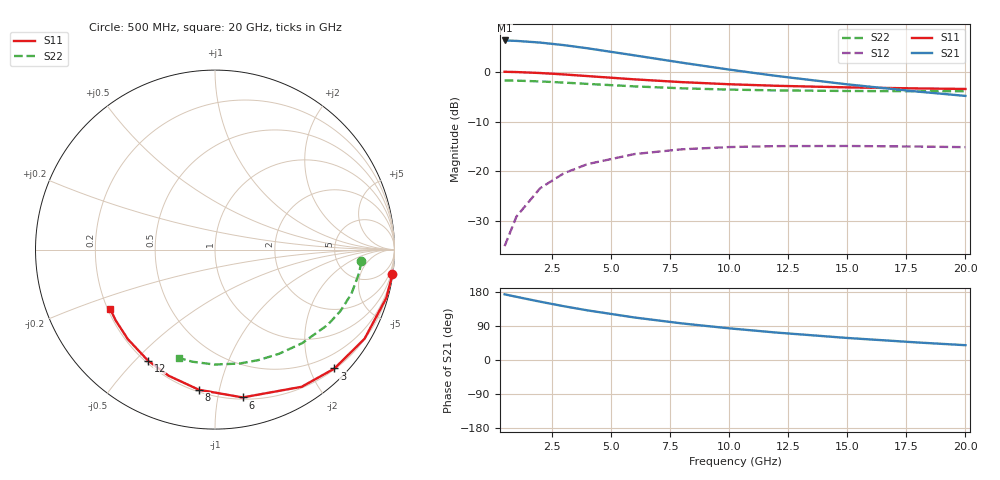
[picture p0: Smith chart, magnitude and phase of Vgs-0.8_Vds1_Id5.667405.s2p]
# Hz S RI R 50
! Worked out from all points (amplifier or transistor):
!   12 points, 500 MHz to 20 GHz, reference 50 ohm
!   highest |S21| = 6.3 dB at 500 MHz (marker M1)
!   |S21| within 3 dB of that: start of sweep to 6.01 GHz
!   unconditionally stable (mu >= 1): 13.79 GHz to end of sweep
!   at 2 GHz: K = 0.13, MSG = 14.6 dB, |S12| = -23.4 dB
!   at 8 GHz: K = 0.56, MSG = 8.7 dB, |S12| = -15.6 dB
!   at 20 GHz: K = 1.57, MAG = 0.7 dB, |S12| = -15.1 dB
!   S11 on the Smith chart (normalised r, x): 500 MHz: 0, -15; 3 GHz: 0.21, -2.41; 6 GHz: 0.21, -1.18; 8 GHz: 0.21, -0.87; 12 GHz: 0.21, -0.54; 20 GHz: 0.21, -0.25
5e8  0.9885 -0.1369  -2.044 0.2388  0.00174 0.0177  0.8153 -0.0656
1e9  0.9551 -0.2682  -1.983 0.4674  0.0068 0.0346  0.8035 -0.1295
2e9  0.8333 -0.4966  -1.761 0.8607  0.0251 0.0629  0.7599 -0.2464
3e9  0.6655 -0.6624  -1.456 1.138  0.0501 0.0814  0.6981 -0.3433
4e9  0.4832 -0.7642  -1.128 1.297  0.0768 0.0899  0.6276 -0.4194
6e9  0.154 -0.8237  -0.5496 1.35  0.1227 0.0852  0.4859 -0.5211
8e9  -0.0898 -0.7809  -0.1416 1.224  0.153 0.066  0.3569 -0.5807
1e10  -0.258 -0.7029  0.1174 1.044  0.17 0.0434  0.242 -0.6157
1.2e10  -0.3737 -0.6182  0.2743 0.865  0.178 0.0219  0.1377 -0.6347
1.5e10  -0.4858 -0.4988  0.394 0.6343  0.1799 -0.00531  -0.00303 -0.6405
1.8e10  -0.5537 -0.3939  0.4374 0.4551  0.1756 -0.0262  -0.1265 -0.6245
2e10  -0.5838 -0.3314  0.4439 0.3604  0.1711 -0.0372  -0.1996 -0.6043
